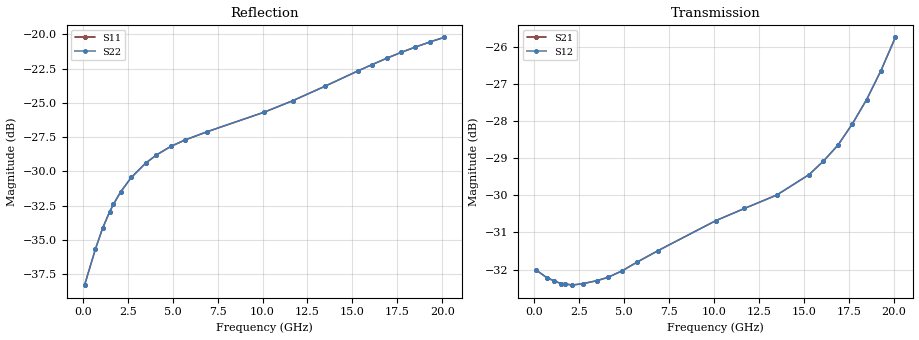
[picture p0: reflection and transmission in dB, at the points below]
!version-1
!date-07.2020
!Series
#	GHZ S RI R 50.0
!	FREQ.GHZ	S11RE	S11IM	S21RE	S21IM	S12RE	S12IM	S22RE	S22IM
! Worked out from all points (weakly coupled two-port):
!   101 points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, 100 MHz to 20.1 GHz, reference 50 ohm
!   highest |S21| = -25.74 dB at 20.1 GHz (marker M1); lowest = -32.4 dB at 2.1 GHz (marker M2)
!   lowest |S11| = -38.3 dB at 100 MHz (marker M3), VSWR 1.02, Z = 49.7 - j1.17 ohm
!   |S11| at or under -10 dB: start of sweep to end of sweep
!   |S22| runs from -38.3 to -20.2 dB; largest |S21 - S12| = 0
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0.1  -0.0033 -0.0117  0.0249 -0.00314  0.0249 -0.00314  -0.0033 -0.0117
0.7  -0.00993 -0.0131  0.0244 -0.00216  0.0244 -0.00216  -0.00993 -0.0131
1.1  -0.0138 -0.0139  0.0242 -0.00172  0.0242 -0.00172  -0.0138 -0.0139
1.5  -0.0173 -0.0145  0.024 -0.00143  0.024 -0.00143  -0.0173 -0.0145
1.7  -0.0189 -0.0147  0.024 -0.00134  0.024 -0.00134  -0.0189 -0.0147
2.1  -0.0218 -0.0152  0.0239 -0.00126  0.0239 -0.00126  -0.0218 -0.0152
2.7  -0.0257 -0.0156  0.024 -0.00136  0.024 -0.00136  -0.0257 -0.0156
3.5  -0.0299 -0.016  0.0242 -0.00182  0.0242 -0.00182  -0.0299 -0.016
4.1  -0.0326 -0.016  0.0244 -0.00238  0.0244 -0.00238  -0.0326 -0.016
4.9  -0.0356 -0.016  0.0248 -0.00332  0.0248 -0.00332  -0.0356 -0.016
5.7  -0.0381 -0.0157  0.0253 -0.00442  0.0253 -0.00442  -0.0381 -0.0157
6.9  -0.0414 -0.0152  0.0259 -0.00625  0.0259 -0.00625  -0.0414 -0.0152
10.1  -0.0504 -0.013  0.027 -0.0112  0.027 -0.0112  -0.0504 -0.013
11.7  -0.0562 -0.0115  0.0272 -0.0135  0.0272 -0.0135  -0.0562 -0.0115
13.5  -0.0642 -0.00893  0.0272 -0.0162  0.0272 -0.0162  -0.0642 -0.00893
15.3  -0.0734 -0.00482  0.0276 -0.0194  0.0276 -0.0194  -0.0734 -0.00482
16.1  -0.0776 -0.00223  0.028 -0.0213  0.028 -0.0213  -0.0776 -0.00223
16.9  -0.0818 0.000978  0.0286 -0.0234  0.0286 -0.0234  -0.0818 0.000978
17.7  -0.0858 0.00493  0.0296 -0.0261  0.0296 -0.0261  -0.0858 0.00493
18.5  -0.0894 0.00976  0.0309 -0.0293  0.0309 -0.0293  -0.0894 0.00976
19.3  -0.0925 0.0156  0.0327 -0.0332  0.0327 -0.0332  -0.0925 0.0156
20.1  -0.0949 0.0227  0.0351 -0.0379  0.0351 -0.0379  -0.0949 0.0227
